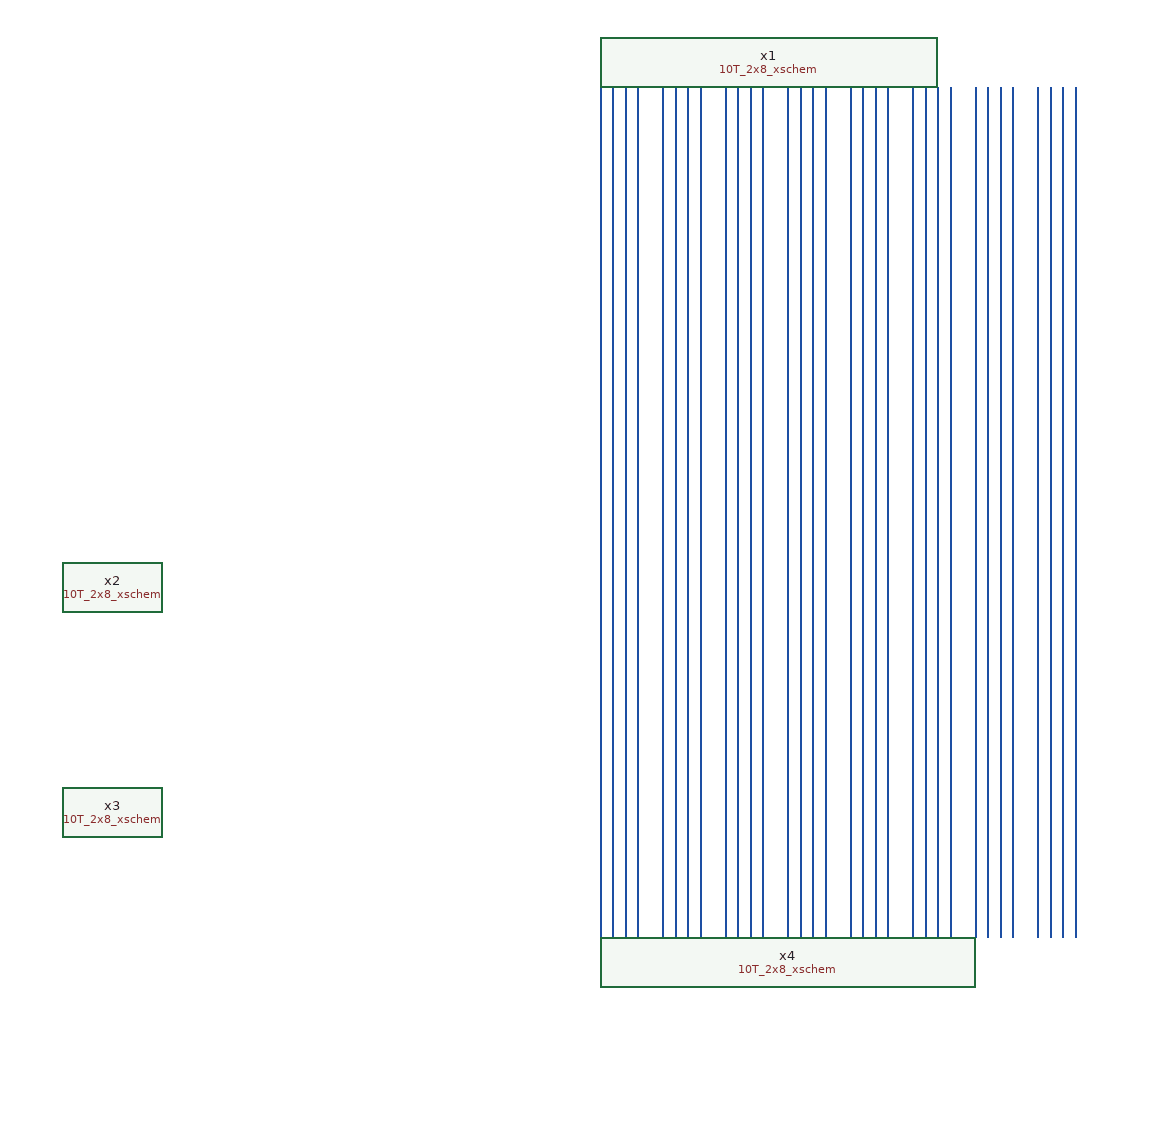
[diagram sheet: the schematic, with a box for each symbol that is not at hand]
v {xschem version=3.0.0 file_version=1.2 }
G {}
K {}
V {}
S {}
E {}
N 340 -430 340 250 {
lab=#net1}
N 370 -430 370 250 {
lab=#net2}
N 360 -430 360 250 {
lab=#net3}
N 350 -430 350 250 {
lab=#net4}
N 400 -430 400 250 {
lab=#net5}
N 410 -430 410 250 {
lab=#net6}
N 420 -430 420 250 {
lab=#net7}
N 390 -430 390 250 {
lab=#net8}
N 440 -430 440 250 {
lab=#net9}
N 450 -430 450 250 {
lab=#net10}
N 460 -430 460 250 {
lab=#net11}
N 470 -430 470 250 {
lab=#net12}
N 490 -430 490 250 {
lab=#net13}
N 500 -430 500 250 {
lab=#net14}
N 510 -430 510 250 {
lab=#net15}
N 520 -430 520 250 {
lab=#net16}
N 540 -430 540 250 {
lab=#net17}
N 550 -430 550 250 {
lab=#net18}
N 560 -430 560 250 {
lab=#net19}
N 570 -430 570 250 {
lab=#net20}
N 590 -430 590 250 {
lab=#net21}
N 600 -430 600 250 {
lab=#net22}
N 610 -430 610 250 {
lab=#net23}
N 620 -430 620 250 {
lab=#net24}
N 640 -430 640 250 {
lab=#net25}
N 650 -430 650 250 {
lab=#net26}
N 660 -430 660 250 {
lab=#net27}
N 670 -430 670 250 {
lab=#net28}
N 690 -430 690 250 {
lab=#net29}
N 700 -430 700 250 {
lab=#net30}
N 710 -430 710 250 {
lab=#net31}
N 720 -430 720 250 {
lab=#net32}
C {10T_2x8_xschem.sym} -50 -210 0 0 {name=x1}
C {10T_2x8_xschem.sym} -50 -30 0 0 {name=x2}
C {10T_2x8_xschem.sym} -50 150 0 0 {name=x3}
C {10T_2x8_xschem.sym} -50 330 0 0 {name=x4}
